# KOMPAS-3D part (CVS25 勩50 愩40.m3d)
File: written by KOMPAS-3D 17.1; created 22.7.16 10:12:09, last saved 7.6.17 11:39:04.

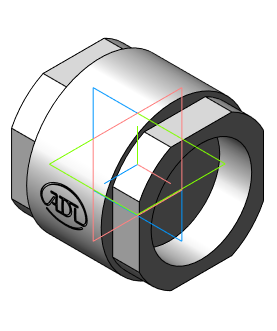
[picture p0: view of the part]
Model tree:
1. Операция без истории:2  (labels: Сталь 20  ГОСТ 1050-88)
